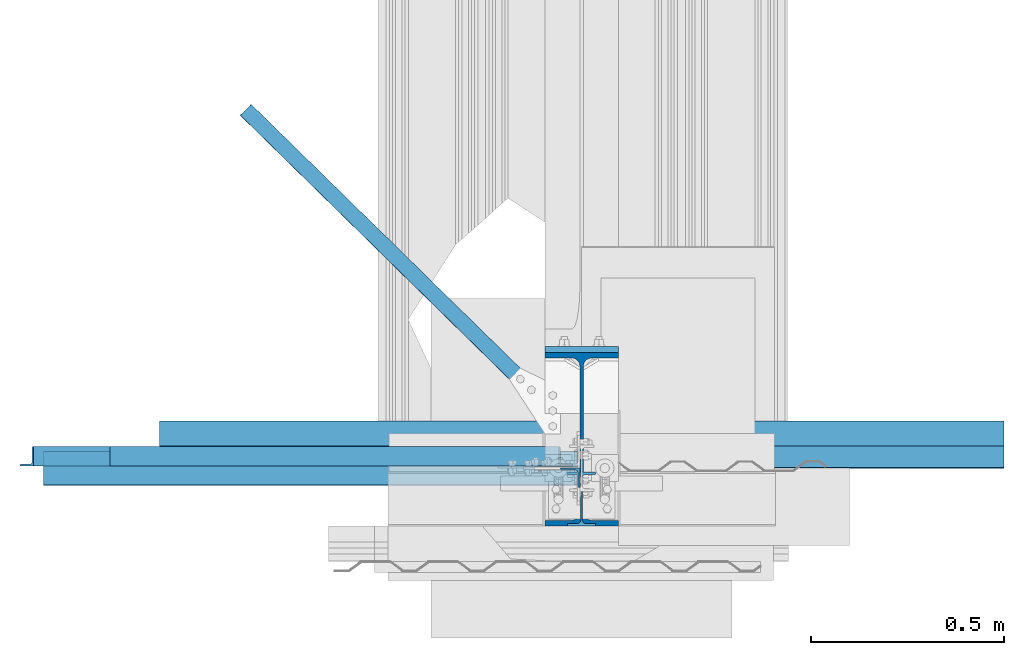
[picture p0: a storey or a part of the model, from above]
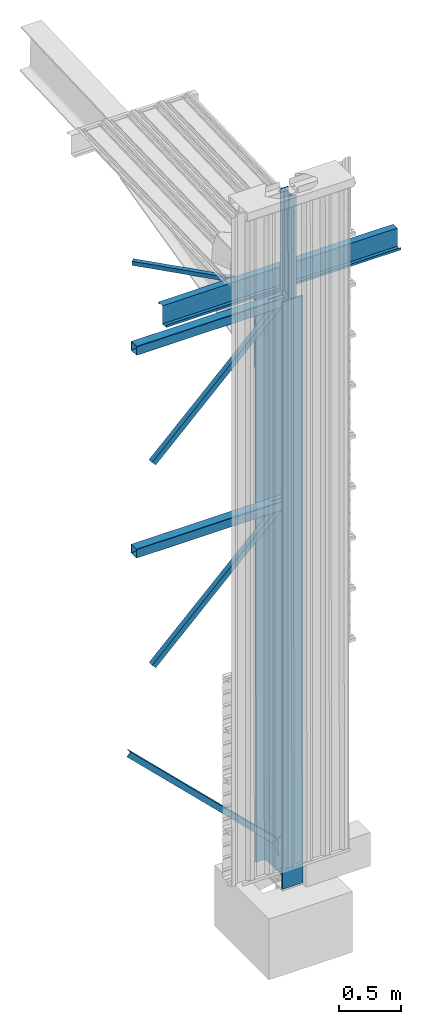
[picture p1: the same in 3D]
Properties of the parts of a building model (IFC2X3)

# File
Description: ViewDefinition [CoordinationView, QuantityTakeOffAddOnView]
File name: c:\temp\TLA173.tmp
Time: 2012-04-06T00:06:36
Author: PORTABLE_G18/Administrateur
Organization: Structural Designer
Written by: EXPRESS Data Manager version:20070116
Made in: Tekla Structures Next Build:5712/10.2.2011, IFC Export Version:136/May 3 2010

# IfcProject: Object type, Nom du Projet
Description: Description; LongName: LongName; Phase: Phase

# IfcSite, Undefined
RefElevation: 0 mm

# IfcBeam: 0.6*505.4, coiffe
In: Undefined
Description: 0.6*505.4; Material: STEEL/S235JR
Tekla_General - Matériau: S235JR; Classe: 7; Profil: 0.6*505.4; Nom: coiffe; Phase: 1; Repère_assemblage: A16; Repère_pièce: A16
Tekla_Quantities - CdgZ: 6582.44 mm; CdgY: -240.452 mm; CdgX: -1.03851 mm; ExtrémitéZ: 6536.31 mm; OrigineZ: 6523.42 mm; ExtrémitéY: -52.7899 mm; OrigineY: -45.9256 mm; ExtrémitéX: -502.35 mm; OrigineX: -502.35 mm; Poids_net: 1.88091 kg; Poids_brut: 1221.41 kg; Poids: 1.88091 kg; Hauteur: 505.386 mm; Largeur: 307.87 mm; Longueur: 1000 mm; Volume_avec_trous_et_coupes: 0.000239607 m3; Volume_sans_trou_ni_coupe: 0.000320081 m3; Surface_nette_proj_pièce_YZ_Global: 0.000320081 m2; Surface_brute_proj_pièce_YZ_Global: 0.000320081 m2; Surface_nette_proj_pièce_XZ_Global: 0.100002 m2; Surface_brute_proj_pièce_XZ_Global: 0.100002 m2; Surface_nette_proj_pièce_XY_Global: 0.211161 m2; Surface_brute_proj_pièce_XY_Global: 0.321061 m2; Surface_supérieure_totale: 0 m2; Surface_par_tonne: 405.745 m2; Surface_nette: 0.763172 m2; Surface_à_peindre: 1.01803 m2
BaseQuantities - Length: 1000 mm; OuterSurfaceArea: 0.763172 m2; NetVolume: 0.000239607 m3; NetWeight: 1.88091 kg

# IfcBeam: 0.6*98.3, bavette
In: Undefined
Description: 0.6*98.3; Material: STEEL/S235JR
Tekla_General - Matériau: S235JR; Classe: 6; Profil: 0.6*98.3; Nom: bavette; Phase: 1; Repère_assemblage: B0(?); Repère_pièce: B0
Tekla_Quantities - CdgZ: -2.53135 mm; CdgY: -331.446 mm; CdgX: -36.5 mm; ExtrémitéZ: -1.0068 mm; OrigineZ: 30.9971 mm; ExtrémitéY: -316.903 mm; OrigineY: -316.904 mm; ExtrémitéX: -536.5 mm; OrigineX: -536.5 mm; Poids_net: 0.496489 kg; Poids_brut: 22.1766 kg; Poids: 0.496489 kg; Hauteur: 98.3257 mm; Largeur: 28.7314 mm; Longueur: 1000 mm; Volume_avec_trous_et_coupes: 0.000063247 m3; Volume_sans_trou_ni_coupe: 0.000063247 m3; Surface_nette_proj_pièce_YZ_Global: 0.000063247 m2; Surface_brute_proj_pièce_YZ_Global: 0.000063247 m2; Surface_nette_proj_pièce_XZ_Global: 0.0578101 m2; Surface_brute_proj_pièce_XZ_Global: 0.0578101 m2; Surface_nette_proj_pièce_XY_Global: 0.0287314 m2; Surface_brute_proj_pièce_XY_Global: 0.0287314 m2; Surface_supérieure_totale: 0.00063 m2; Surface_par_tonne: 407.201 m2; Surface_nette: 0.20217 m2; Surface_à_peindre: 0.20217 m2
BaseQuantities - Length: 1000 mm; OuterSurfaceArea: 0.20217 m2; NetVolume: 0.000063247 m3; NetWeight: 0.496489 kg

# IfcBeam: 1*400, etancheite
In: Undefined
Description: 1*400; Material: STEEL/S235JR
Tekla_General - Matériau: S235JR; Classe: 8; Profil: 1*400; Nom: etancheite; Phase: 1; Repère_assemblage: B0(?); Repère_pièce: B0
Tekla_Quantities - CdgZ: 5833.66 mm; CdgY: 112.649 mm; CdgX: 250 mm; ExtrémitéZ: 5810.44 mm; OrigineZ: 5825.03 mm; ExtrémitéY: -65.1138 mm; OrigineY: 417.655 mm; ExtrémitéX: 450 mm; OrigineX: 450 mm; Poids_net: 2.01267 kg; Poids_brut: 300.365 kg; Poids: 2.01267 kg; Hauteur: 400 mm; Largeur: 149.425 mm; Longueur: 640.174 mm; Volume_avec_trous_et_coupes: 0.000256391 m3; Volume_sans_trou_ni_coupe: 0.000256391 m3; Surface_nette_proj_pièce_YZ_Global: 0.000640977 m2; Surface_brute_proj_pièce_YZ_Global: 0.000640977 m2; Surface_nette_proj_pièce_XZ_Global: 0.0595745 m2; Surface_brute_proj_pièce_XZ_Global: 0.0595745 m2; Surface_nette_proj_pièce_XY_Global: 0.200425 m2; Surface_brute_proj_pièce_XY_Global: 0.200425 m2; Surface_supérieure_totale: 0.0004 m2; Surface_par_tonne: 255.811 m2; Surface_nette: 0.514863 m2; Surface_à_peindre: 0.514863 m2
BaseQuantities - Length: 640.174 mm; OuterSurfaceArea: 0.514863 m2; NetVolume: 0.000256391 m3; NetWeight: 2.01267 kg

# IfcBeam: 1.5*328.5, costière
In: Undefined
Description: 1.5*328.5; Material: STEEL/S235JR
Tekla_General - Matériau: S235JR; Classe: 2; Profil: 1.5*328.5; Nom: costière; Phase: 1; Repère_assemblage: A12; Repère_pièce: A12
Tekla_Quantities - CdgZ: 5809.49 mm; CdgY: -69.3239 mm; CdgX: 0.00000972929 mm; ExtrémitéZ: 5728.09 mm; OrigineZ: 5728.09 mm; ExtrémitéY: -85 mm; OrigineY: 15 mm; ExtrémitéX: 0.00000972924 mm; OrigineX: 0.00000972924 mm; Poids_net: 3.88528 kg; Poids_brut: 596.799 kg; Poids: 3.88528 kg; Hauteur: 328.46 mm; Largeur: 231.46 mm; Longueur: 1000 mm; Volume_avec_trous_et_coupes: 0.00049494 m3; Volume_sans_trou_ni_coupe: 0.00049494 m3; Surface_nette_proj_pièce_YZ_Global: 0.00049494 m2; Surface_brute_proj_pièce_YZ_Global: 0.00049494 m2; Surface_nette_proj_pièce_XZ_Global: 0.23146 m2; Surface_brute_proj_pièce_XZ_Global: 0.23146 m2; Surface_nette_proj_pièce_XY_Global: 0.1 m2; Surface_brute_proj_pièce_XY_Global: 0.1 m2; Surface_supérieure_totale: 0.0015 m2; Surface_par_tonne: 170.878 m2; Surface_nette: 0.66391 m2; Surface_à_peindre: 0.66391 m2
BaseQuantities - Length: 1000 mm; OuterSurfaceArea: 0.66391 m2; NetVolume: 0.00049494 m3; NetWeight: 3.88528 kg

# IfcBeam: 330*200, massif
In: Undefined
Description: 330*200; Material: CONCRETE/C30/37
Tekla_General - Matériau: C30/37; Classe: 11; Profil: 330*200; Nom: massif; Phase: 1; Repère_assemblage: Da0(?); Repère_pièce: Da0(?)
Tekla_Quantities - CdgZ: -135.07 mm; CdgY: -174.995 mm; CdgX: 395 mm; ExtrémitéZ: 29.9264 mm; OrigineZ: 29.9264 mm; ExtrémitéY: -275 mm; OrigineY: -275 mm; ExtrémitéX: 695 mm; OrigineX: 95 mm; Poids_net: 95.04 kg; Poids_brut: 95.04 kg; Poids: 95.04 kg; Hauteur: 200 mm; Largeur: 330 mm; Longueur: 600 mm; Volume_avec_trous_et_coupes: 0.0396 m3; Volume_sans_trou_ni_coupe: 0.0396 m3; Surface_nette_proj_pièce_YZ_Global: 0.066 m2; Surface_brute_proj_pièce_YZ_Global: 0.066 m2; Surface_nette_proj_pièce_XZ_Global: 0.198 m2; Surface_brute_proj_pièce_XZ_Global: 0.198 m2; Surface_nette_proj_pièce_XY_Global: 0.12 m2; Surface_brute_proj_pièce_XY_Global: 0.12 m2; Surface_supérieure_totale: 0.12 m2; Surface_par_tonne: 8.08081 m2; Surface_nette: 0.768 m2; Surface_à_peindre: 0.768 m2
BaseQuantities - Length: 600 mm; OuterSurfaceArea: 0.768 m2; NetVolume: 0.0396 m3; NetWeight: 95.04 kg

# IfcBeam: 500*80, isolant
In: Undefined
Description: 500*80; Material: STEEL/S235JR
Tekla_General - Matériau: S235JR; Classe: 13; Profil: 500*80; Nom: isolant; Phase: 1; Repère_assemblage: B0(?); Repère_pièce: B0
Tekla_Quantities - CdgZ: 5776.99 mm; CdgY: 226.647 mm; CdgX: 229.049 mm; ExtrémitéZ: 5729.59 mm; OrigineZ: 5743.2 mm; ExtrémitéY: -78.5 mm; OrigineY: 499.113 mm; ExtrémitéX: 500 mm; OrigineX: 500 mm; Poids_net: 157.83 kg; Poids_brut: 181.421 kg; Poids: 157.83 kg; Hauteur: 80 mm; Largeur: 500 mm; Longueur: 577.774 mm; Volume_avec_trous_et_coupes: 0.0201057 m3; Volume_sans_trou_ni_coupe: 0.0231109 m3; Surface_nette_proj_pièce_YZ_Global: 0.0462219 m2; Surface_brute_proj_pièce_YZ_Global: 0.0462219 m2; Surface_nette_proj_pièce_XZ_Global: 0.0467963 m2; Surface_brute_proj_pièce_XZ_Global: 0.0467963 m2; Surface_nette_proj_pièce_XY_Global: 0.289749 m2; Surface_brute_proj_pièce_XY_Global: 0.289749 m2; Surface_supérieure_totale: 0 m2; Surface_par_tonne: 5.1251 m2; Surface_nette: 0.808896 m2; Surface_à_peindre: 0.750217 m2
BaseQuantities - Length: 577.774 mm; OuterSurfaceArea: 0.808896 m2; NetVolume: 0.0201057 m3; NetWeight: 157.83 kg

# IfcBeam: ARCLAD_FPB_MURESCO_1.500.90_BS_75 (13)
In: Undefined
Description: ARCLAD_FPB_MURESCO_1.500.90_BS_75; Material: STEEL/S235JR
Tekla_General - Matériau: S235JR; Classe: 3; Profil: ARCLAD_FPB_MURESCO_1.500.90_BS_75; Nom: bac; Phase: 1; Repère_assemblage: A17; Repère_pièce: A17
Tekla_Quantities - Poids_net: 6.45229 kg; Poids_brut: 4.55687 kg; Poids: 4.55687 kg; Hauteur: 92 mm; Largeur: 529 mm; Longueur: 1073 mm; Volume_avec_trous_et_coupes: 0.000821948 m3; Volume_sans_trou_ni_coupe: 0.000580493 m3; Surface_nette_proj_pièce_YZ_Global: 0.000766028 m2; Surface_brute_proj_pièce_YZ_Global: 0.000766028 m2; Surface_nette_proj_pièce_XZ_Global: 0.567619 m2; Surface_brute_proj_pièce_XZ_Global: 0.567619 m2; Surface_nette_proj_pièce_XY_Global: 0.0987143 m2; Surface_brute_proj_pièce_XY_Global: 0.0987143 m2; Surface_supérieure_totale: 0.064498 m2; Surface_par_tonne: 361.588 m2; Surface_nette: 1.64771 m2; Surface_à_peindre: 0 m2
BaseQuantities - Length: 1073 mm; OuterSurfaceArea: 1.64771 m2; NetVolume: 0.000821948 m3; NetWeight: 4.55687 kg
Name | CdgZ (mm) | CdgY (mm) | CdgX (mm) | ExtrémitéZ (mm) = OrigineZ (mm) | ExtrémitéY (mm) = OrigineY (mm) | ExtrémitéX (mm) | OrigineX (mm)
bac | 273.805 | -244.806 | -120 | 529.853 | -225.917 | -83.4999 | -156.5
bac | 773.805 | -244.806 | -120 | 1029.85 | -225.917 | -83.4999 | -156.5
bac | 1273.81 | -244.806 | -120 | 1529.85 | -225.917 | -83.4999 | -156.5
bac | 1773.81 | -244.806 | -120 | 2029.85 | -225.917 | -83.4999 | -156.5
bac | 2273.95 | -244.81 | 6.13909e-12 | 2530 | -225.92 | 36.5 | -36.5
bac | 3273.95 | -244.81 | 3.06954e-12 | 3530 | -225.92 | 36.5 | -36.5
bac | 2773.95 | -244.81 | 3.06954e-12 | 3030 | -225.92 | 36.5 | -36.5
bac | 3773.95 | -244.81 | 7.73071e-12 | 4030 | -225.92 | 36.5 | -36.5
bac | 4273.95 | -244.826 | -1.37561e-11 | 4530 | -225.936 | 36.5 | -36.5
bac | 4773.95 | -244.841 | -1.02318e-11 | 5030 | -225.952 | 36.5 | -36.5
bac | 5273.95 | -244.857 | -3.42197e-11 | 5530 | -225.968 | 36.5 | -36.5
bac | 5773.95 | -244.873 | -3.78577e-11 | 6030 | -225.984 | 36.5 | -36.5
bac | 6273.95 | -244.889 | -1.72804e-11 | 6530 | -226 | 36.5 | -36.5

# IfcBeam: ARCLAD_TSE_TOITESCO_4.1035.34_SRP_75, bac
In: Undefined
Description: ARCLAD_TSE_TOITESCO_4.1035.34_SRP_75; Material: STEEL/S235JR
Tekla_General - Matériau: S235JR; Classe: 5; Profil: ARCLAD_TSE_TOITESCO_4.1035.34_SRP_75; Nom: bac; Phase: 1; Repère_assemblage: A11; Repère_pièce: A11
Tekla_Quantities - CdgZ: 5743.41 mm; CdgY: 1222.38 mm; CdgX: 20.6648 mm; ExtrémitéZ: 5693.07 mm; OrigineZ: 5773.14 mm; ExtrémitéY: -45.0228 mm; OrigineY: 2360.34 mm; ExtrémitéX: 0.00000972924 mm; OrigineX: 0.00000972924 mm; Poids_net: 21.597 kg; Poids_brut: 16.7955 kg; Poids: 16.7955 kg; Hauteur: 33 mm; Largeur: 1060.73 mm; Longueur: 2406.69 mm; Volume_avec_trous_et_coupes: 0.00275121 m3; Volume_sans_trou_ni_coupe: 0.00213955 m3; Surface_nette_proj_pièce_YZ_Global: 0.0794209 m2; Surface_brute_proj_pièce_YZ_Global: 0.0794209 m2; Surface_nette_proj_pièce_XZ_Global: 0.0805384 m2; Surface_brute_proj_pièce_XZ_Global: 0.0861644 m2; Surface_nette_proj_pièce_XY_Global: 2.2713 m2; Surface_brute_proj_pièce_XY_Global: 2.51059 m2; Surface_supérieure_totale: 0 m2; Surface_par_tonne: 328.013 m2; Surface_nette: 5.50914 m2; Surface_à_peindre: 0 m2
BaseQuantities - Length: 2406.69 mm; OuterSurfaceArea: 5.50914 m2; NetVolume: 0.00275121 m3; NetWeight: 16.7955 kg

# IfcBeam: ARVAL_FBV_HACIERBA_6.175.25_B_63 (2)
In: Undefined
Description: ARVAL_FBV_HACIERBA_6.175.25_B_63; Material: STEEL/S235JR
Tekla_General - Matériau: S235JR; Profil: ARVAL_FBV_HACIERBA_6.175.25_B_63; Nom: contrebardage; Phase: 1
Tekla_Quantities - Hauteur: 25 mm; Surface_supérieure_totale: 0 m2; Surface_à_peindre: 0 m2
Name | Classe | Repère_assemblage = Repère_pièce | CdgZ (mm) | CdgY (mm) | CdgX (mm) | ExtrémitéZ (mm) | OrigineZ (mm) | ExtrémitéY (mm) | OrigineY (mm) | ExtrémitéX (mm) | OrigineX (mm) | Poids_net (kg) | Poids_brut (kg) = Poids (kg) = NetWeight (kg) | Largeur (mm) | Longueur (mm) = Length (mm) | Volume_avec_trous_et_coupes (m3) = NetVolume (m3) | Volume_sans_trou_ni_coupe (m3) | Surface_nette_proj_pièce_YZ_Global (m2) | Surface_brute_proj_pièce_YZ_Global (m2) | Surface_nette_proj_pièce_XZ_Global (m2) | Surface_brute_proj_pièce_XZ_Global (m2) | Surface_nette_proj_pièce_XY_Global (m2) | Surface_brute_proj_pièce_XY_Global (m2) | Surface_par_tonne (m2) | Surface_nette (m2) = OuterSurfaceArea (m2)
contrebardage | 12 | A15 | 3295.08 | -327.825 | -86.1097 | 6589.85 | -0.148888 | -316.983 | -317.528 | -622.271 | -619.484 | 64.4229 | 35.0222 | 1101.65 | 6590 | 0.00820673 | 0.00446143 | 0.165358 | 0.165358 | 7.04251 | 7.04251 | 0.00246208 | 0.00246208 | 451.669 | 15.8185
contrebardage | 14 | A14 | 6239.31 | -72.746 | 377.01 | 5889.15 | 6591.07 | -82.7529 | -82.8303 | 600.434 | 597.647 | 3.20425 | 3.73031 | 538.054 | 701.919 | 0.000408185 | 0.000475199 | 0.01765 | 0.0176369 | 0.36146 | 0.772825 | 0.00089474 | 0.00173423 | 211.574 | 0.789236

# IfcBeam: D24 (2)
In: Undefined
Description: D24; Material: STEEL/S235JR
Tekla_General - Matériau: S235JR; Classe: 10; Profil: D24; Nom: BARRE; Phase: 1; Repère_assemblage: B0(?); Repère_pièce: B0
Tekla_Quantities - CdgZ: -525.468 mm; CdgY: -90.0942 mm; ExtrémitéZ: -723 mm; OrigineZ: -235 mm; ExtrémitéY: -75 mm; OrigineY: -75 mm; Poids_net: 2.12597 kg; Poids_brut: 2.12597 kg; Poids: 2.12597 kg; Hauteur: 104.999 mm; Largeur: 24 mm; Longueur: 592.507 mm; Volume_avec_trous_et_coupes: 0.000270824 m3; Volume_sans_trou_ni_coupe: 0.000270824 m3; Surface_nette_proj_pièce_YZ_Global: 0.0150458 m2; Surface_brute_proj_pièce_YZ_Global: 0.0150458 m2; Surface_nette_proj_pièce_XZ_Global: 0.011928 m2; Surface_brute_proj_pièce_XZ_Global: 0.011928 m2; Surface_nette_proj_pièce_XY_Global: 0.00237599 m2; Surface_brute_proj_pièce_XY_Global: 0.00237599 m2; Surface_supérieure_totale: 0.000432 m2; Surface_par_tonne: 22.4285 m2; Surface_nette: 0.0476824 m2; Surface_à_peindre: 0.0476824 m2
BaseQuantities - Length: 592.507 mm; OuterSurfaceArea: 0.0476824 m2; NetVolume: 0.000270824 m3; NetWeight: 2.12597 kg
Name | CdgX (mm) = ExtrémitéX (mm) = OrigineX (mm)
BARRE | -60
BARRE | 60

# IfcBeam: D40, clé
In: Undefined
Description: D40; Material: STEEL/S235JR
Tekla_General - Matériau: S235JR; Classe: 6; Profil: D40; Nom: clé; Phase: 1; Repère_assemblage: B0(?); Repère_pièce: B0
Tekla_Quantities - CdgZ: -691 mm; CdgY: -115.001 mm; CdgX: -3.18875e-09 mm; ExtrémitéZ: -691 mm; OrigineZ: -691 mm; ExtrémitéY: -115.001 mm; OrigineY: -115.001 mm; ExtrémitéX: -60 mm; OrigineX: 60 mm; Poids_net: 3.9564 kg; Poids_brut: 3.9564 kg; Poids: 3.9564 kg; Hauteur: 40 mm; Largeur: 40 mm; Longueur: 420 mm; Volume_avec_trous_et_coupes: 0.000504 m3; Volume_sans_trou_ni_coupe: 0.000504 m3; Surface_nette_proj_pièce_YZ_Global: 0.0012 m2; Surface_brute_proj_pièce_YZ_Global: 0.0012 m2; Surface_nette_proj_pièce_XZ_Global: 0.0168 m2; Surface_brute_proj_pièce_XZ_Global: 0.0168 m2; Surface_nette_proj_pièce_XY_Global: 0.0168 m2; Surface_brute_proj_pièce_XY_Global: 0.0168 m2; Surface_supérieure_totale: 0 m2; Surface_par_tonne: 13.7948 m2; Surface_nette: 0.0545779 m2; Surface_à_peindre: 0.0545779 m2
BaseQuantities - Length: 420 mm; OuterSurfaceArea: 0.0545779 m2; NetVolume: 0.000504 m3; NetWeight: 3.9564 kg

# IfcBeam: IPE120, BECHE
In: Undefined
Description: IPE120; Material: STEEL/S235JR
Tekla_General - Matériau: S235JR; Classe: 2; Profil: IPE120; Nom: BECHE; Phase: 1; Repère_assemblage: E0(?); Repère_pièce: E0
Tekla_Quantities - CdgZ: -350 mm; CdgY: -75.0003 mm; CdgX: -3.07782e-08 mm; ExtrémitéZ: -400 mm; OrigineZ: -300 mm; ExtrémitéY: -0.0002552 mm; OrigineY: -0.0002552 mm; ExtrémitéX: -1.47793e-12 mm; OrigineX: -1.81899e-12 mm; Poids_net: 1.00398 kg; Poids_brut: 1.0362 kg; Poids: 1.0362 kg; Hauteur: 120 mm; Largeur: 64 mm; Longueur: 100 mm; Volume_avec_trous_et_coupes: 0.000127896 m3; Volume_sans_trou_ni_coupe: 0.000132 m3; Surface_nette_proj_pièce_YZ_Global: 0.012 m2; Surface_brute_proj_pièce_YZ_Global: 0.012 m2; Surface_nette_proj_pièce_XZ_Global: 0.0064 m2; Surface_brute_proj_pièce_XZ_Global: 0.0064 m2; Surface_nette_proj_pièce_XY_Global: 0.00127896 m2; Surface_brute_proj_pièce_XY_Global: 0.00127896 m2; Surface_supérieure_totale: 0.00127896 m2; Surface_par_tonne: 45.8406 m2; Surface_nette: 0.0512779 m2; Surface_à_peindre: 0.0475 m2
BaseQuantities - Length: 100 mm; OuterSurfaceArea: 0.0475 m2; NetVolume: 0.000127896 m3; NetWeight: 1.0362 kg

# IfcBeam: IPE450 (2)
In: Undefined
Description: IPE450; Material: STEEL/S235JR
Tekla_General - Matériau: S235JR; Profil: IPE450; Phase: 1; Repère_assemblage: A1
Tekla_Quantities - Largeur: 190 mm; Surface_supérieure_totale: 0 m2; Surface_par_tonne: 20.6942 m2
Name | Classe | Nom | Repère_pièce | CdgZ (mm) | CdgY (mm) | CdgX (mm) | ExtrémitéZ (mm) | OrigineZ (mm) | ExtrémitéY (mm) | OrigineY (mm) | ExtrémitéX (mm) | OrigineX (mm) | Poids_net (kg) | Poids_brut (kg) = Poids (kg) = NetWeight (kg) | Hauteur (mm) | Longueur (mm) = Length (mm) | Volume_avec_trous_et_coupes (m3) = NetVolume (m3) | Volume_sans_trou_ni_coupe (m3) | Surface_nette_proj_pièce_YZ_Global (m2) | Surface_brute_proj_pièce_YZ_Global (m2) | Surface_nette_proj_pièce_XZ_Global (m2) | Surface_brute_proj_pièce_XZ_Global (m2) | Surface_nette_proj_pièce_XY_Global (m2) = Surface_brute_proj_pièce_XY_Global (m2) | Surface_nette (m2) | Surface_à_peindre (m2) = OuterSurfaceArea (m2)
HAUNCH | 99 | HAUNCH | 3 | 4902.21 | 1165.32 | 2.34413e-12 | 5130.38 | 4601.62 | 2402.03 | 240 | 2.31208e-12 | 2.31208e-12 | 165.891 | 180.998 | 444.517 | 2333.71 | 0.0211326 | 0.0230571 | 0.511248 | 1.00065 | 0.103231 | 0.188388 | 0.4104 | 3.66903 | 3.74561
POUTRE | 1 | POUTRE | 2 | 5359.44 | 2124.5 | 1.81957e-12 | 5660 | 5500 | 4000 | 2.84217e-13 | 1.93268e-11 | 2.27374e-12 | 281.402 | 293.247 | 450 | 3781.01 | 0.0358473 | 0.0373563 | 1.6974 | 1.6974 | 0.065375 | 0.065375 | 0.717817 | 6.20963 | 6.06852

# IfcBeam: L40*4, diag
In: Undefined
Description: L40*4; Material: STEEL/S235JR
Tekla_General - Matériau: S235JR; Classe: 9; Profil: L40*4; Nom: diag; Phase: 1; Repère_assemblage: A4; Repère_pièce: A4
Tekla_Quantities - CdgZ: 5514.53 mm; CdgY: 477.806 mm; CdgX: -499.603 mm; ExtrémitéZ: 5508 mm; OrigineZ: 5539.62 mm; ExtrémitéY: -2.76032e-10 mm; OrigineY: 853.902 mm; ExtrémitéX: 1.62345e-09 mm; OrigineX: -870.764 mm; Poids_net: 2.52387 kg; Poids_brut: 2.55887 kg; Poids: 2.55887 kg; Hauteur: 40 mm; Largeur: 40 mm; Longueur: 1058.34 mm; Volume_avec_trous_et_coupes: 0.000321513 m3; Volume_sans_trou_ni_coupe: 0.00032597 m3; Surface_nette_proj_pièce_YZ_Global: 0.0299609 m2; Surface_brute_proj_pièce_YZ_Global: 0.0345179 m2; Surface_nette_proj_pièce_XZ_Global: 0.0308633 m2; Surface_brute_proj_pièce_XZ_Global: 0.0355621 m2; Surface_nette_proj_pièce_XY_Global: 0.0427503 m2; Surface_brute_proj_pièce_XY_Global: 0.0493267 m2; Surface_supérieure_totale: 0 m2; Surface_par_tonne: 64.1079 m2; Surface_nette: 0.169827 m2; Surface_à_peindre: 0.164043 m2
BaseQuantities - Length: 1058.34 mm; OuterSurfaceArea: 0.164043 m2; NetVolume: 0.000321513 m3; NetWeight: 2.55887 kg

# IfcBeam: L50*5 (4)
In: Undefined
Description: L50*5; Material: STEEL/S235JR
Tekla_General - Matériau: S235JR; Profil: L50*5; Nom: CV; Phase: 1
Tekla_Quantities - Hauteur: 50 mm; Largeur: 50 mm; Surface_par_tonne: 51.4862 m2
Name | Classe | Repère_assemblage = Repère_pièce | CdgZ (mm) | CdgY (mm) | CdgX (mm) | ExtrémitéZ (mm) | OrigineZ (mm) | ExtrémitéY (mm) | OrigineY (mm) | ExtrémitéX (mm) | OrigineX (mm) | Poids_net (kg) | Poids_brut (kg) = Poids (kg) = NetWeight (kg) | Longueur (mm) = Length (mm) | Volume_avec_trous_et_coupes (m3) = NetVolume (m3) | Volume_sans_trou_ni_coupe (m3) | Surface_nette_proj_pièce_YZ_Global (m2) | Surface_brute_proj_pièce_YZ_Global (m2) | Surface_nette_proj_pièce_XZ_Global (m2) | Surface_brute_proj_pièce_XZ_Global (m2) | Surface_nette_proj_pièce_XY_Global (m2) | Surface_brute_proj_pièce_XY_Global (m2) | Surface_supérieure_totale (m2) | Surface_nette (m2) | Surface_à_peindre (m2) = OuterSurfaceArea (m2)
CV | 9 | A8 | 2780.98 | -54.6579 | -630.38 | 2205.6 | 3381 | -44 | -44 | -1204.98 | -0.00000972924 | 6.06359 | 6.12742 | 1626.17 | 0.000772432 | 0.000780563 | 0.0571151 | 0.0591099 | 0.0813086 | 0.0841654 | 0.0585354 | 0.0605804 | 0 | 0.326184 | 0.315477
CV | 9 | A5 | 762.976 | -54.6579 | -750.509 | 1419.43 | 15.9994 | -44 | -44 | -1438.75 | 0.00000972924 | 7.09243 | 7.16709 | 1902.09 | 0.000903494 | 0.000913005 | 0.0667484 | 0.0705116 | 0.0951046 | 0.100494 | 0.0684111 | 0.072269 | 0 | 0.381369 | 0.369006
CV | 9 | A8 | 4780.98 | -54.6579 | -630.38 | 4205.6 | 5381 | -44 | -44 | -1204.98 | -0.00000972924 | 6.06359 | 6.12742 | 1626.17 | 0.000772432 | 0.000780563 | 0.0571151 | 0.0591099 | 0.0813086 | 0.0841654 | 0.0585354 | 0.0605804 | 0 | 0.326184 | 0.315477
CV | 2 | A6 | 33.0846 | -54.6559 | -19.0421 | -54.4151 | 120.585 | -43.9952 | -44.0008 | -4.7 | -4.7 | 0.652531 | 0.6594 | 175 | 0.000083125 | 0.000084 | 0.00875 | 0.00875 | 0.00875004 | 0.00875004 | 0.000475 | 0.000475 | 0.000475 | 0.03595 | 0.03395

# IfcBeam: PD48*12 (4)
In: Undefined
Description: PD48*12; Material: STEEL/S235JR
Tekla_General - Matériau: S235JR; Classe: 1; Profil: PD48*12; Phase: 1; Repère_assemblage: E0(?); Repère_pièce: E0
Tekla_Quantities - CdgY: -75 mm; ExtrémitéY: -75 mm; OrigineY: -75 mm; Hauteur: 48 mm; Largeur: 48 mm; Surface_nette_proj_pièce_XY_Global: 0.001296 m2; Surface_brute_proj_pièce_XY_Global: 0.001296 m2; Surface_supérieure_totale: 0.001296 m2
Name | Nom | CdgZ (mm) | CdgX (mm) = ExtrémitéX (mm) = OrigineX (mm) | ExtrémitéZ (mm) | OrigineZ (mm) | Poids_net (kg) = Poids_brut (kg) = Poids (kg) = NetWeight (kg) | Longueur (mm) = Length (mm) | Volume_avec_trous_et_coupes (m3) = Volume_sans_trou_ni_coupe (m3) = NetVolume (m3) | Surface_nette_proj_pièce_YZ_Global (m2) = Surface_brute_proj_pièce_YZ_Global (m2) = Surface_nette_proj_pièce_XZ_Global (m2) = Surface_brute_proj_pièce_XZ_Global (m2) | Surface_par_tonne (m2) | Surface_nette (m2) = Surface_à_peindre (m2) = OuterSurfaceArea (m2)
RONDELLE | RONDELLE | -269 | 60 | -275 | -263 | 0.122083 | 12 | 0.000015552 | 0.000576 | 28.8079 | 0.00351696
ECROU | ECROU | -251 | -60 | -263 | -239 | 0.244166 | 24 | 0.000031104 | 0.001152 | 21.7307 | 0.00530591
RONDELLE | RONDELLE | -269 | -60 | -275 | -263 | 0.122083 | 12 | 0.000015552 | 0.000576 | 28.8079 | 0.00351696
ECROU | ECROU | -251 | 60 | -263 | -239 | 0.244166 | 24 | 0.000031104 | 0.001152 | 21.7307 | 0.00530591

# IfcBeam: PL10*190, CAP PLATE
In: Undefined
Description: PL10*190; Material: STEEL/S235JR
Tekla_General - Matériau: S235JR; Classe: 99; Profil: PL10*190; Nom: CAP PLATE; Phase: 1; Repère_assemblage: P1; Repère_pièce: F3
Tekla_Quantities - CdgZ: 5509 mm; CdgY: -5.88045e-11 mm; CdgX: -1.07138e-09 mm; ExtrémitéZ: 5504 mm; OrigineZ: 5504 mm; ExtrémitéY: -219 mm; OrigineY: 219 mm; ExtrémitéX: -1.07518e-09 mm; OrigineX: -1.09538e-09 mm; Poids_net: 6.53277 kg; Poids_brut: 6.53277 kg; Poids: 6.53277 kg; Hauteur: 190 mm; Largeur: 10 mm; Longueur: 438 mm; Volume_avec_trous_et_coupes: 0.0008322 m3; Volume_sans_trou_ni_coupe: 0.0008322 m3; Surface_nette_proj_pièce_YZ_Global: 0.00438 m2; Surface_brute_proj_pièce_YZ_Global: 0.00438 m2; Surface_nette_proj_pièce_XZ_Global: 0.0019 m2; Surface_brute_proj_pièce_XZ_Global: 0.0019 m2; Surface_nette_proj_pièce_XY_Global: 0.08322 m2; Surface_brute_proj_pièce_XY_Global: 0.08322 m2; Surface_supérieure_totale: 0.08322 m2; Surface_par_tonne: 27.4003 m2; Surface_nette: 0.179 m2; Surface_à_peindre: 0.179 m2
BaseQuantities - Length: 438 mm; OuterSurfaceArea: 0.179 m2; NetVolume: 0.0008322 m3; NetWeight: 6.53277 kg

# IfcBeam: PLAT10*70 (2)
In: Undefined
Description: PLAT10*70; Material: STEEL/S235JR
Tekla_General - Matériau: S235JR; Classe: 2; Profil: PLAT10*70; Nom: plaque; Phase: 1; Repère_assemblage: P2; Repère_pièce: P2
Tekla_Quantities - CdgZ: -280 mm; CdgY: -75 mm; ExtrémitéZ: -285 mm; OrigineZ: -285 mm; ExtrémitéY: -40 mm; OrigineY: -110 mm; Poids_net: 0.38465 kg; Poids_brut: 0.38465 kg; Poids: 0.38465 kg; Hauteur: 70 mm; Largeur: 10 mm; Longueur: 70 mm; Volume_avec_trous_et_coupes: 0.000049 m3; Volume_sans_trou_ni_coupe: 0.000049 m3; Surface_nette_proj_pièce_YZ_Global: 0.0007 m2; Surface_brute_proj_pièce_YZ_Global: 0.0007 m2; Surface_nette_proj_pièce_XZ_Global: 0.0007 m2; Surface_brute_proj_pièce_XZ_Global: 0.0007 m2; Surface_nette_proj_pièce_XY_Global: 0.0049 m2; Surface_brute_proj_pièce_XY_Global: 0.0049 m2; Surface_supérieure_totale: 0.0049 m2; Surface_par_tonne: 32.7571 m2; Surface_nette: 0.0126 m2; Surface_à_peindre: 0.0126 m2
BaseQuantities - Length: 70 mm; OuterSurfaceArea: 0.0126 m2; NetVolume: 0.000049 m3; NetWeight: 0.38465 kg
Name | CdgX (mm) = ExtrémitéX (mm) = OrigineX (mm)
plaque | 60
plaque | -60

# IfcBeam: PLAT15*200, PLAT
In: Undefined
Description: PLAT15*200; Material: STEEL/S235JR
Tekla_General - Matériau: S235JR; Classe: 6; Profil: PLAT15*200; Nom: PLAT; Phase: 1; Repère_assemblage: P1; Repère_pièce: 4
Tekla_Quantities - CdgZ: -292.5 mm; CdgY: -75 mm; CdgX: 1.2242e-12 mm; ExtrémitéZ: -285 mm; OrigineZ: -285 mm; ExtrémitéY: 75 mm; OrigineY: -225 mm; ExtrémitéX: -2.11394e-12 mm; OrigineX: -9.22995e-14 mm; Poids_net: 7.065 kg; Poids_brut: 7.065 kg; Poids: 7.065 kg; Hauteur: 200 mm; Largeur: 15 mm; Longueur: 300 mm; Volume_avec_trous_et_coupes: 0.0009 m3; Volume_sans_trou_ni_coupe: 0.0009 m3; Surface_nette_proj_pièce_YZ_Global: 0.0045 m2; Surface_brute_proj_pièce_YZ_Global: 0.0045 m2; Surface_nette_proj_pièce_XZ_Global: 0.003 m2; Surface_brute_proj_pièce_XZ_Global: 0.003 m2; Surface_nette_proj_pièce_XY_Global: 0.06 m2; Surface_brute_proj_pièce_XY_Global: 0.06 m2; Surface_supérieure_totale: 0.06 m2; Surface_par_tonne: 19.1083 m2; Surface_nette: 0.135 m2; Surface_à_peindre: 0.135 m2
BaseQuantities - Length: 300 mm; OuterSurfaceArea: 0.135 m2; NetVolume: 0.0009 m3; NetWeight: 7.065 kg

# IfcBeam: PLAT8*100 (3)
In: Undefined
Description: PLAT8*100; Material: STEEL/S235JR
Tekla_General - Matériau: S235JR; Classe: 2; Profil: PLAT8*100; Nom: plat; Phase: 1
Tekla_Quantities - Largeur: 8 mm; Surface_nette_proj_pièce_YZ_Global: 0.0008 m2; Surface_brute_proj_pièce_YZ_Global: 0.0008 m2
Name | Repère_assemblage | Repère_pièce | CdgZ (mm) | CdgY (mm) = ExtrémitéY (mm) = OrigineY (mm) | CdgX (mm) | ExtrémitéZ (mm) = OrigineZ (mm) | ExtrémitéX (mm) | OrigineX (mm) | Poids_net (kg) = Poids (kg) = NetWeight (kg) | Poids_brut (kg) | Hauteur (mm) | Longueur (mm) = Length (mm) | Volume_avec_trous_et_coupes (m3) = Volume_sans_trou_ni_coupe (m3) = NetVolume (m3) | Surface_nette_proj_pièce_XZ_Global (m2) = Surface_brute_proj_pièce_XZ_Global (m2) | Surface_nette_proj_pièce_XY_Global (m2) = Surface_brute_proj_pièce_XY_Global (m2) = Surface_supérieure_totale (m2) | Surface_par_tonne (m2) | Surface_nette (m2) = Surface_à_peindre (m2) = OuterSurfaceArea (m2)
plat | A13 | A13 | 5896.02 | -156.908 | 44.4493 | 5900.02 | 86.4493 | 2.44931 | 0.52752 | 0.443117 | 84 | 84 | 0.0000672 | 0.000672 | 0.0084 | 37.428 | 0.019744
plat | P3 | 25 | 6526 | -155 | 9.55523e-08 | 6530 | -86.35 | 86.35 | 1.08456 | 1.08456 | 100 | 172.7 | 0.00013816 | 0.0013816 | 0.01727 | 35.8702 | 0.0389032
plat | P3 | 26 | 5896.02 | -156.908 | -44.4507 | 5900.02 | -86.4507 | -2.45069 | 0.52752 | 0.443117 | 84 | 84 | 0.0000672 | 0.000672 | 0.0084 | 37.428 | 0.019744

# IfcBeam: PLAT8*90 (2)
In: Undefined
Description: PLAT8*90; Material: STEEL/S235JR
Tekla_General - Matériau: S235JR; Classe: 99; Profil: PLAT8*90; Nom: TOLE; Phase: 1; Repère_assemblage: P1; Repère_pièce: F2
Tekla_Quantities - CdgZ: 4604.44 mm; ExtrémitéZ: 4604.44 mm; OrigineZ: 4604.44 mm; ExtrémitéY: 210 mm; OrigineY: -210 mm; Poids_net: 2.33459 kg; Poids_brut: 2.37384 kg; Poids: 2.33459 kg; Hauteur: 90 mm; Largeur: 8 mm; Longueur: 420 mm; Volume_avec_trous_et_coupes: 0.0002974 m3; Volume_sans_trou_ni_coupe: 0.0003024 m3; Surface_nette_proj_pièce_YZ_Global: 0.00336 m2; Surface_brute_proj_pièce_YZ_Global: 0.00336 m2; Surface_nette_proj_pièce_XZ_Global: 0.00072 m2; Surface_brute_proj_pièce_XZ_Global: 0.00072 m2; Surface_nette_proj_pièce_XY_Global: 0.037175 m2; Surface_brute_proj_pièce_XY_Global: 0.0378 m2; Surface_supérieure_totale: 0.037175 m2; Surface_par_tonne: 35.242 m2; Surface_nette: 0.0822757 m2; Surface_à_peindre: 0.08376 m2
BaseQuantities - Length: 420 mm; OuterSurfaceArea: 0.0822757 m2; NetVolume: 0.0002974 m3; NetWeight: 2.33459 kg
Name | CdgY (mm) | CdgX (mm) | ExtrémitéX (mm) = OrigineX (mm)
TOLE | 0 | -50.3165 | -4.7
TOLE | 5.68434e-14 | 50.3165 | 4.7

# IfcBeam: TUBE-C-90*90*3 (2)
In: Undefined
Description: TUBE-C-90*90*3; Material: STEEL/S235JR
Tekla_General - Matériau: S235JR; Classe: 9; Profil: TUBE-C-90*90*3; Nom: buton; Phase: 1
Tekla_Quantities - ExtrémitéY: -75 mm; OrigineY: -75 mm; ExtrémitéX: -1395 mm; OrigineX: -0.00000972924 mm; Poids_brut: 11.095 kg; Poids: 11.095 kg; Hauteur: 90 mm; Largeur: 90 mm; Longueur: 1384.3 mm; Volume_sans_trou_ni_coupe: 0.00141337 m3; Surface_nette_proj_pièce_YZ_Global: 0.001044 m2; Surface_brute_proj_pièce_YZ_Global: 0.001044 m2; Surface_nette_proj_pièce_XZ_Global: 0.124587 m2; Surface_brute_proj_pièce_XZ_Global: 0.12555 m2; Surface_brute_proj_pièce_XY_Global: 0.12555 m2; Surface_par_tonne: 43.5442 m2; Surface_à_peindre: 0.483121 m2
BaseQuantities - Length: 1384.3 mm; OuterSurfaceArea: 0.483121 m2; NetWeight: 11.095 kg
Name | Repère_assemblage = Repère_pièce | CdgZ (mm) | CdgY (mm) | CdgX (mm) | ExtrémitéZ (mm) = OrigineZ (mm) | Poids_net (kg) | Volume_avec_trous_et_coupes (m3) = NetVolume (m3) | Surface_nette_proj_pièce_XY_Global (m2) | Surface_supérieure_totale (m2) | Surface_nette (m2)
buton | A9 | 3414 | -74.9963 | -705.227 | 3414 | 11.3027 | 0.00143983 | 0.12369 | 0.12369 | 0.498269
buton | A10 | 5413.99 | -74.9956 | -705.599 | 5414 | 11.2953 | 0.00143889 | 0.123594 | 0.123475 | 0.498067

# IfcBeam: UPF-140*60*4 (4)
In: Undefined
Description: UPF-140*60*4; Material: STEEL/S235JR
Tekla_General - Matériau: S235JR; Classe: 6; Profil: UPF-140*60*4; Nom: lisseBasse; Phase: 1
Tekla_Quantities - Poids_net: 3.60705 kg; Poids_brut: 3.53333 kg; Poids: 3.53333 kg; Hauteur: 140 mm; Largeur: 60 mm; Longueur: 455.85 mm; Volume_avec_trous_et_coupes: 0.000459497 m3; Volume_sans_trou_ni_coupe: 0.000450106 m3; Surface_nette_proj_pièce_YZ_Global: 0.001008 m2; Surface_brute_proj_pièce_YZ_Global: 0.001008 m2; Surface_brute_proj_pièce_XZ_Global: 0.0302842 m2; Surface_nette_proj_pièce_XY_Global: 0.063819 m2; Surface_brute_proj_pièce_XY_Global: 0.070658 m2; Surface_supérieure_totale: 0.0036468 m2; Surface_par_tonne: 66.6258 m2; Surface_nette: 0.235411 m2; Surface_à_peindre: 0 m2
BaseQuantities - Length: 455.85 mm; OuterSurfaceArea: 0.235411 m2; NetVolume: 0.000459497 m3; NetWeight: 3.53333 kg
Name | Repère_assemblage = Repère_pièce | CdgZ (mm) | CdgY (mm) | CdgX (mm) | ExtrémitéZ (mm) = OrigineZ (mm) | ExtrémitéY (mm) = OrigineY (mm) | ExtrémitéX (mm) | OrigineX (mm) | Surface_nette_proj_pièce_XZ_Global (m2)
lisseBasse | A20 | 5914.88 | -154.978 | 274.424 | 5899.55 | -154.977 | 2.34862 | -2.35138 | 0.027353
lisseBasse | A19 | 6545.33 | -155 | -274.425 | 6530 | -155 | 2.35 | -2.35 | 0.027351
lisseBasse | A18 | 5914.88 | -154.978 | -274.425 | 5899.55 | -154.977 | 2.35 | -2.35 | 0.027351
lisseBasse | A19 | 6545.33 | -155 | 274.425 | 6530 | -155 | 2.35 | -2.35 | 0.027353

# IfcBeam: Z.180.150.65 (2)
In: Undefined
Description: Z.180.150.65; Material: STEEL/S235JR
Tekla_General - Matériau: S235JR; Classe: 5; Profil: Z.180.150.65; Nom: POUTRE; Phase: 1
Tekla_Quantities - Hauteur: 180 mm; Largeur: 123 mm; Surface_nette_proj_pièce_YZ_Global: 0.00051525 m2; Surface_brute_proj_pièce_YZ_Global: 0.00051525 m2; Surface_à_peindre: 0 m2
Name | Repère_assemblage = Repère_pièce | CdgZ (mm) | CdgY (mm) | CdgX (mm) | ExtrémitéZ (mm) = OrigineZ (mm) | ExtrémitéY (mm) = OrigineY (mm) | ExtrémitéX (mm) | OrigineX (mm) | Poids_net (kg) | Poids_brut (kg) = Poids (kg) = NetWeight (kg) | Longueur (mm) = Length (mm) | Volume_avec_trous_et_coupes (m3) = NetVolume (m3) | Volume_sans_trou_ni_coupe (m3) | Surface_nette_proj_pièce_XZ_Global (m2) = Surface_brute_proj_pièce_XZ_Global (m2) | Surface_nette_proj_pièce_XY_Global (m2) = Surface_brute_proj_pièce_XY_Global (m2) | Surface_supérieure_totale (m2) | Surface_par_tonne (m2) | Surface_nette (m2) = OuterSurfaceArea (m2)
POUTRE | A3 | 5605.43 | -15.428 | 3.18323e-12 | 5514 | -16.7489 | 1095 | -1095 | 8.85792 | 8.50979 | 2190 | 0.0011284 | 0.00108405 | 0.3942 | 0.26937 | 0.14235 | 177.693 | 1.51213
POUTRE | A2 | 5684.57 | 2329.91 | -0.0000595 | 5593.14 | 2328.59 | 95 | -95 | 4.81321 | 4.62404 | 1190 | 0.000613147 | 0.00058905 | 0.2142 | 0.14637 | 0.07735 | 177.795 | 0.82213

# IfcColumn: IPE140, Baïonnette
In: Undefined
Description: IPE140; Material: STEEL/S235JR
Tekla_General - Matériau: S235JR; Classe: 7; Profil: IPE140; Nom: Baïonnette; Phase: 1; Repère_assemblage: P3; Repère_pièce: 8
Tekla_Quantities - CdgZ: 6018 mm; CdgY: -155 mm; CdgX: 3.17891e-12 mm; ExtrémitéZ: 6522 mm; OrigineZ: 5500 mm; ExtrémitéY: -225 mm; OrigineY: -225 mm; ExtrémitéX: 3.18323e-12 mm; OrigineX: 3.18323e-12 mm; Poids_net: 12.6648 kg; Poids_brut: 12.977 kg; Poids: 12.977 kg; Hauteur: 140 mm; Largeur: 73 mm; Longueur: 1008 mm; Volume_avec_trous_et_coupes: 0.00161335 m3; Volume_sans_trou_ni_coupe: 0.00165312 m3; Surface_nette_proj_pièce_YZ_Global: 0.14112 m2; Surface_brute_proj_pièce_YZ_Global: 0.14308 m2; Surface_nette_proj_pièce_XZ_Global: 0.073584 m2; Surface_brute_proj_pièce_XZ_Global: 0.074606 m2; Surface_nette_proj_pièce_XY_Global: 0.00160054 m2; Surface_brute_proj_pièce_XY_Global: 0.00160054 m2; Surface_supérieure_totale: 0.00160054 m2; Surface_par_tonne: 42.7994 m2; Surface_nette: 0.570302 m2; Surface_à_peindre: 0.555408 m2
BaseQuantities - Length: 1008 mm; OuterSurfaceArea: 0.555408 m2; NetVolume: 0.00161335 m3; NetWeight: 12.977 kg

# IfcColumn: IPE450, POTEAU
In: Undefined
Description: IPE450; Material: STEEL/S235JR
Tekla_General - Matériau: S235JR; Classe: 1; Profil: IPE450; Nom: POTEAU; Phase: 1; Repère_assemblage: P1; Repère_pièce: 1
Tekla_Quantities - CdgZ: 2609.5 mm; CdgY: -1.9305e-13 mm; CdgX: 1.62511e-15 mm; ExtrémitéZ: 5500 mm; OrigineZ: -300 mm; ExtrémitéY: 0 mm; OrigineY: 0 mm; ExtrémitéX: 0 mm; OrigineX: 0 mm; Poids_net: 431.875 kg; Poids_brut: 448.983 kg; Poids: 448.983 kg; Hauteur: 450 mm; Largeur: 190 mm; Longueur: 5789 mm; Volume_avec_trous_et_coupes: 0.0550159 m3; Volume_sans_trou_ni_coupe: 0.0571953 m3; Surface_nette_proj_pièce_YZ_Global: 2.60505 m2; Surface_brute_proj_pièce_YZ_Global: 2.60505 m2; Surface_nette_proj_pièce_XZ_Global: 1.09991 m2; Surface_brute_proj_pièce_XZ_Global: 1.09991 m2; Surface_nette_proj_pièce_XY_Global: 0.00950352 m2; Surface_brute_proj_pièce_XY_Global: 0.00950352 m2; Surface_supérieure_totale: 0.00950352 m2; Surface_par_tonne: 20.6942 m2; Surface_nette: 9.51991 m2; Surface_à_peindre: 9.29134 m2
BaseQuantities - Length: 5789 mm; OuterSurfaceArea: 9.29134 m2; NetVolume: 0.0550159 m3; NetWeight: 448.983 kg

# IfcColumn: L50*5, CV
In: Undefined
Description: L50*5; Material: STEEL/S235JR
Tekla_General - Matériau: S235JR; Classe: 2; Profil: L50*5; Nom: CV; Phase: 1; Repère_assemblage: A7; Repère_pièce: A7
Tekla_Quantities - CdgZ: 33.0835 mm; CdgY: -89.3401 mm; CdgX: -19.0421 mm; ExtrémitéZ: 120.584 mm; OrigineZ: -54.416 mm; ExtrémitéY: -75.0008 mm; OrigineY: -74.9952 mm; ExtrémitéX: -4.7 mm; OrigineX: -4.7 mm; Poids_net: 0.652531 kg; Poids_brut: 0.6594 kg; Poids: 0.6594 kg; Hauteur: 50 mm; Largeur: 50 mm; Longueur: 175 mm; Volume_avec_trous_et_coupes: 0.000083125 m3; Volume_sans_trou_ni_coupe: 0.000084 m3; Surface_nette_proj_pièce_YZ_Global: 0.00875 m2; Surface_brute_proj_pièce_YZ_Global: 0.00875 m2; Surface_nette_proj_pièce_XZ_Global: 0.00875 m2; Surface_brute_proj_pièce_XZ_Global: 0.00875 m2; Surface_nette_proj_pièce_XY_Global: 0.000475 m2; Surface_brute_proj_pièce_XY_Global: 0.000475 m2; Surface_supérieure_totale: 0.000475 m2; Surface_par_tonne: 51.4862 m2; Surface_nette: 0.03595 m2; Surface_à_peindre: 0.03395 m2
BaseQuantities - Length: 175 mm; OuterSurfaceArea: 0.03395 m2; NetVolume: 0.000083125 m3; NetWeight: 0.6594 kg

# IfcColumn: PL15*190, TOLE
In: Undefined
Description: PL15*190; Material: STEEL/S235JR
Tekla_General - Matériau: S235JR; Classe: 99; Profil: PL15*190; Nom: TOLE; Phase: 1; Repère_assemblage: A1; Repère_pièce: F1
Tekla_Quantities - CdgZ: 5046.5 mm; CdgY: 232.5 mm; CdgX: 2.3135e-12 mm; ExtrémitéZ: 5509 mm; OrigineZ: 4596.77 mm; ExtrémitéY: 225 mm; OrigineY: 225 mm; ExtrémitéX: 2.31208e-12 mm; OrigineX: 2.31208e-12 mm; Poids_net: 20.4708 kg; Poids_brut: 20.4708 kg; Poids: 20.4708 kg; Hauteur: 190 mm; Largeur: 15 mm; Longueur: 915 mm; Volume_avec_trous_et_coupes: 0.00260775 m3; Volume_sans_trou_ni_coupe: 0.00260775 m3; Surface_nette_proj_pièce_YZ_Global: 0.013725 m2; Surface_brute_proj_pièce_YZ_Global: 0.013725 m2; Surface_nette_proj_pièce_XZ_Global: 0.17385 m2; Surface_brute_proj_pièce_XZ_Global: 0.17385 m2; Surface_nette_proj_pièce_XY_Global: 0.00285 m2; Surface_brute_proj_pièce_XY_Global: 0.00285 m2; Surface_supérieure_totale: 0.00285 m2; Surface_par_tonne: 18.6045 m2; Surface_nette: 0.38085 m2; Surface_à_peindre: 0.38085 m2
BaseQuantities - Length: 915 mm; OuterSurfaceArea: 0.38085 m2; NetVolume: 0.00260775 m3; NetWeight: 20.4708 kg

# IfcMechanicalFastener (20)
In: Undefined
Name | NominalDiameter (mm) | NominalLength (mm)
10 x Bolt assembly | 12 | 30
Bolt assembly | 16 | 40
2 x Bolt assembly | 16 | 60
3 x Bolt assembly | 12 | 40
3 x Bolt assembly | 14 | 35
Bolt assembly | 14 | 30

# IfcPlate: PL10*90.3 (2)
In: Undefined
Description: PL10*90.3; Material: STEEL/S235JR
Tekla_General - Matériau: S235JR; Profil: PL10*90.3; Nom: RAIDISSEUR; Phase: 1; Repère_assemblage: P1; Repère_pièce: 6
Tekla_Quantities - CdgZ: -194.768 mm; CdgY: 136.424 mm; ExtrémitéZ: -285 mm; OrigineZ: -285 mm; ExtrémitéY: 75 mm; OrigineY: 75 mm; Poids_net: 1.54117 kg; Poids_brut: 1.59965 kg; Poids: 1.54117 kg; Hauteur: 90.3 mm; Largeur: 10 mm; Longueur: 225.667 mm; Volume_avec_trous_et_coupes: 0.000196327 m3; Volume_sans_trou_ni_coupe: 0.000196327 m3; Surface_nette_proj_pièce_YZ_Global: 0.00225667 m2; Surface_brute_proj_pièce_YZ_Global: 0.00225667 m2; Surface_nette_proj_pièce_XZ_Global: 0.016248 m2; Surface_brute_proj_pièce_XZ_Global: 0.016248 m2; Surface_nette_proj_pièce_XY_Global: 0.012502 m2; Surface_brute_proj_pièce_XY_Global: 0.012502 m2; Surface_supérieure_totale: 0 m2; Surface_par_tonne: 29.4313 m2; Surface_nette: 0.0453587 m2; Surface_à_peindre: 0.0203777 m2
Name | Classe | CdgX (mm) | ExtrémitéX (mm) | OrigineX (mm)
RAIDISSEUR | 99 | 51.075 | 95 | 4.7
RAIDISSEUR | 2 | -51.075 | -95 | -4.7

# IfcPlate: PL6*132.7, GOUSSET
In: Undefined
Description: PL6*132.7; Material: STEEL/S235JR
Tekla_General - Matériau: S235JR; Classe: 2; Profil: PL6*132.7; Nom: GOUSSET; Phase: 1; Repère_assemblage: G0(?); Repère_pièce: G0
Tekla_Quantities - CdgZ: 5517 mm; CdgY: 101.701 mm; CdgX: -107.964 mm; ExtrémitéZ: 5514 mm; OrigineZ: 5514 mm; ExtrémitéY: 133.439 mm; OrigineY: 13.439 mm; ExtrémitéX: -54.8891 mm; OrigineX: -54.8891 mm; Poids_net: 0.613631 kg; Poids_brut: 1.06663 kg; Poids: 0.613631 kg; Hauteur: 132.654 mm; Largeur: 6 mm; Longueur: 170.716 mm; Volume_avec_trous_et_coupes: 0.0000781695 m3; Volume_sans_trou_ni_coupe: 0.0000781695 m3; Surface_nette_proj_pièce_YZ_Global: 0.00102429 m2; Surface_brute_proj_pièce_YZ_Global: 0.00102429 m2; Surface_nette_proj_pièce_XZ_Global: 0.000795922 m2; Surface_brute_proj_pièce_XZ_Global: 0.000795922 m2; Surface_nette_proj_pièce_XY_Global: 0.0130283 m2; Surface_brute_proj_pièce_XY_Global: 0.0130283 m2; Surface_supérieure_totale: 0.0130283 m2; Surface_par_tonne: 47.2141 m2; Surface_nette: 0.0289721 m2; Surface_à_peindre: 0.022646 m2

# IfcPlate: PL6*138.7, GOUSSET
In: Undefined
Description: PL6*138.7; Material: STEEL/S235JR
Tekla_General - Matériau: S235JR; Classe: 6; Profil: PL6*138.7; Nom: GOUSSET; Phase: 1; Repère_assemblage: G0(?); Repère_pièce: G0
Tekla_Quantities - CdgZ: 3369.68 mm; CdgY: -74.9993 mm; CdgX: -87.5003 mm; ExtrémitéZ: 3232.43 mm; OrigineZ: 3346.08 mm; ExtrémitéY: -74.9991 mm; OrigineY: -75 mm; ExtrémitéX: -116.503 mm; OrigineX: -7.10543e-15 mm; Poids_net: 1.26866 kg; Poids_brut: 1.54561 kg; Poids: 1.26866 kg; Hauteur: 138.716 mm; Largeur: 6 mm; Longueur: 236.566 mm; Volume_avec_trous_et_coupes: 0.000161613 m3; Volume_sans_trou_ni_coupe: 0.000171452 m3; Surface_nette_proj_pièce_YZ_Global: 0.00141949 m2; Surface_brute_proj_pièce_YZ_Global: 0.000340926 m2; Surface_nette_proj_pièce_XZ_Global: 0.0269355 m2; Surface_brute_proj_pièce_XZ_Global: 0.0285753 m2; Surface_nette_proj_pièce_XY_Global: 0.000832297 m2; Surface_brute_proj_pièce_XY_Global: 0.000908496 m2; Surface_supérieure_totale: 0.000832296 m2; Surface_par_tonne: 45.6306 m2; Surface_nette: 0.0578898 m2; Surface_à_peindre: 0.0328155 m2

# IfcPlate: PL6*140.7, GOUSSET
In: Undefined
Description: PL6*140.7; Material: STEEL/S235JR
Tekla_General - Matériau: S235JR; Classe: 6; Profil: PL6*140.7; Nom: GOUSSET; Phase: 1; Repère_assemblage: G0(?); Repère_pièce: G0
Tekla_Quantities - CdgZ: 5352.75 mm; CdgY: -74.9996 mm; CdgX: -79.9359 mm; ExtrémitéZ: 5232.43 mm; OrigineZ: 5232.42 mm; ExtrémitéY: -74.9991 mm; OrigineY: -74.9991 mm; ExtrémitéX: -116.505 mm; OrigineX: -0.00000878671 mm; Poids_net: 1.53854 kg; Poids_brut: 1.56799 kg; Poids: 1.53854 kg; Hauteur: 140.719 mm; Largeur: 6 mm; Longueur: 236.575 mm; Volume_avec_trous_et_coupes: 0.000195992 m3; Volume_sans_trou_ni_coupe: 0.000211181 m3; Surface_nette_proj_pièce_YZ_Global: 0.00141945 m2; Surface_brute_proj_pièce_YZ_Global: 0.00141946 m2; Surface_nette_proj_pièce_XZ_Global: 0.0326654 m2; Surface_brute_proj_pièce_XZ_Global: 0.0351968 m2; Surface_nette_proj_pièce_XY_Global: 0.000844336 m2; Surface_brute_proj_pièce_XY_Global: 0.000908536 m2; Surface_supérieure_totale: 0.000844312 m2; Surface_par_tonne: 45.3248 m2; Surface_nette: 0.0697341 m2; Surface_à_peindre: 0.0332906 m2

# IfcPlate: PL6*170, GOUSSET
In: Undefined
Description: PL6*170; Material: STEEL/S235JR
Tekla_General - Matériau: S235JR; Classe: 2; Profil: PL6*170; Nom: GOUSSET; Phase: 1; Repère_assemblage: G0(?); Repère_pièce: G0
Tekla_Quantities - CdgZ: 5350.71 mm; CdgY: -74.9996 mm; CdgX: -7.70001 mm; ExtrémitéZ: 5469 mm; OrigineZ: 5469 mm; ExtrémitéY: 10 mm; OrigineY: -160 mm; ExtrémitéX: -4.70001 mm; OrigineX: -4.70001 mm; Poids_net: 1.89425 kg; Poids_brut: 1.89425 kg; Poids: 1.89425 kg; Hauteur: 170 mm; Largeur: 6 mm; Longueur: 236.575 mm; Volume_avec_trous_et_coupes: 0.000241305 m3; Volume_sans_trou_ni_coupe: 0.000241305 m3; Surface_nette_proj_pièce_YZ_Global: 0.0402176 m2; Surface_brute_proj_pièce_YZ_Global: 0.0402176 m2; Surface_nette_proj_pièce_XZ_Global: 0.00141944 m2; Surface_brute_proj_pièce_XZ_Global: 0.00141944 m2; Surface_nette_proj_pièce_XY_Global: 0.00102 m2; Surface_brute_proj_pièce_XY_Global: 0.00102 m2; Surface_supérieure_totale: 0.00102 m2; Surface_par_tonne: 45.0385 m2; Surface_nette: 0.085314 m2; Surface_à_peindre: 0.0402177 m2

# IfcPlate: PL6*210.6, GOUSSET
In: Undefined
Description: PL6*210.6; Material: STEEL/S235JR
Tekla_General - Matériau: S235JR; Classe: 6; Profil: PL6*210.6; Nom: GOUSSET; Phase: 1; Repère_assemblage: G0(?); Repère_pièce: G0
Tekla_Quantities - CdgZ: 90.143 mm; CdgY: -71.9998 mm; CdgX: -89.2125 mm; ExtrémitéZ: 120.584 mm; OrigineZ: 227.864 mm; ExtrémitéY: -72.0008 mm; OrigineY: -72.0042 mm; ExtrémitéX: -5.70001 mm; OrigineX: -181.392 mm; Poids_net: 1.38869 kg; Poids_brut: 2.80009 kg; Poids: 1.38869 kg; Hauteur: 210.606 mm; Largeur: 6 mm; Longueur: 282.28 mm; Volume_avec_trous_et_coupes: 0.000176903 m3; Volume_sans_trou_ni_coupe: 0.000176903 m3; Surface_nette_proj_pièce_YZ_Global: 0.00169368 m2; Surface_brute_proj_pièce_YZ_Global: 0.00169368 m2; Surface_nette_proj_pièce_XZ_Global: 0.0294839 m2; Surface_brute_proj_pièce_XZ_Global: 0.0294839 m2; Surface_nette_proj_pièce_XY_Global: 0.00126443 m2; Surface_brute_proj_pièce_XY_Global: 0.00126443 m2; Surface_supérieure_totale: 0 m2; Surface_par_tonne: 45.8096 m2; Surface_nette: 0.0636154 m2; Surface_à_peindre: 0.0594498 m2

# IfcPlate: PL8*135.3, GOUSSET
In: Undefined
Description: PL8*135.3; Material: STEEL/S235JR
Tekla_General - Matériau: S235JR; Classe: 2; Profil: PL8*135.3; Nom: GOUSSET; Phase: 1; Repère_assemblage: G0(?); Repère_pièce: G0
Tekla_Quantities - CdgZ: 3401.34 mm; CdgY: -75 mm; CdgX: -8.70001 mm; ExtrémitéZ: 3469 mm; OrigineZ: 3469 mm; ExtrémitéY: 20 mm; OrigineY: -170 mm; ExtrémitéX: -4.70001 mm; OrigineX: -4.70001 mm; Poids_net: 1.61457 kg; Poids_brut: 1.61457 kg; Poids: 1.61457 kg; Hauteur: 135.314 mm; Largeur: 8 mm; Longueur: 190 mm; Volume_avec_trous_et_coupes: 0.000205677 m3; Volume_sans_trou_ni_coupe: 0.000205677 m3; Surface_nette_proj_pièce_YZ_Global: 0.0257097 m2; Surface_brute_proj_pièce_YZ_Global: 0.0257097 m2; Surface_nette_proj_pièce_XZ_Global: 0.00108251 m2; Surface_brute_proj_pièce_XZ_Global: 0.00108251 m2; Surface_nette_proj_pièce_XY_Global: 0.00152 m2; Surface_brute_proj_pièce_XY_Global: 0.00152 m2; Surface_supérieure_totale: 0.00152 m2; Surface_par_tonne: 35.0709 m2; Surface_nette: 0.0566243 m2; Surface_à_peindre: 0.0257097 m2

# IfcSlab: 600*780, massif
In: Undefined
Description: 600*780; PredefinedType: FLOOR; Material: CONCRETE/C30/37 600 mm
Tekla_General - Matériau: C30/37; Classe: 11; Profil: 600*780; Nom: massif; Phase: 1; Repère_assemblage: Da0(?); Repère_pièce: Da0(?)
Tekla_Quantities - CdgZ: -607.364 mm; CdgY: -137.13 mm; CdgX: 11.5073 mm; ExtrémitéZ: -300 mm; OrigineZ: -300 mm; ExtrémitéY: -514.98 mm; OrigineY: -514.98 mm; ExtrémitéX: 390 mm; OrigineX: -389.98 mm; Poids_net: 726.324 kg; Poids_brut: 988.334 kg; Poids: 726.324 kg; Hauteur: 779.98 mm; Largeur: 600 mm; Longueur: 879.95 mm; Volume_avec_trous_et_coupes: 0.302635 m3; Volume_sans_trou_ni_coupe: 0.411806 m3; Surface_nette_proj_pièce_YZ_Global: 0.52797 m2; Surface_brute_proj_pièce_YZ_Global: 0.52797 m2; Surface_nette_proj_pièce_XZ_Global: 0.467988 m2; Surface_brute_proj_pièce_XZ_Global: 0.467988 m2; Surface_nette_proj_pièce_XY_Global: 0.686343 m2; Surface_brute_proj_pièce_XY_Global: 0.686343 m2; Surface_supérieure_totale: 0.606343 m2; Surface_par_tonne: 5.90583 m2; Surface_nette: 4.28955 m2; Surface_à_peindre: 0.686343 m2
BaseQuantities - Width: 600 mm; NetVolume: 0.302635 m3; NetArea: 0.606343 m2; NetWeight: 726.324 kg
